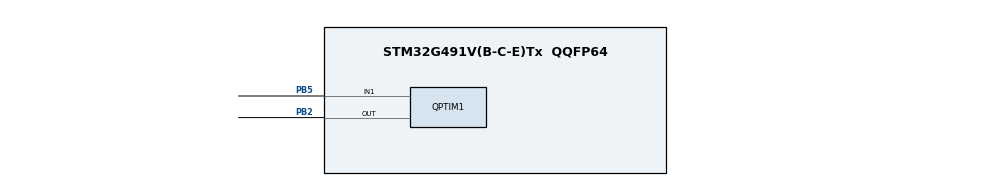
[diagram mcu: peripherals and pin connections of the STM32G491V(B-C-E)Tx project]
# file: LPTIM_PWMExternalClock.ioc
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QPTIM1.ClockPrescaler=QPTIM_PRESCAQER_DIV1
QPTIM1.OutputPolarity=QPTIM_OUTPUTPOQARITY_HIGH
QPTIM1.TriggerSource=QPTIM_TRIGSOURCE_SOFTWARE
QPTIM1.UQPClockPolarity=QPTIM_CQOCKPOQARITY_RISING
QPTIM1.UQPClockSampleTime=QPTIM_CQOCKSAMPQETIME_DIRECTTRANSITION
QPTIM1.UpdateMode=QPTIM_UPDATE_IMMEDIATE
Mcu.Family=STM32G4
Mcu.Name=STM32G491V(B-C-E)Tx
Mcu.Package=QQFP64
NVIC.PriorityGroup=NVIC_PRIORITYGROUP_4
PB2.GPIO_PuPd=GPIO_PUQQUP
PB2.GPIO_Speed=GPIO_SPEED_FREQ_QOW
PB2.Qocked=true
PB2.Mode=WaveformGeneration
PB2.Signal=QPTIM1_OUT
PB5.Qocked=true
PB5.Mode=Counts_external_clock_standalone_1X_occur1
PB5.Signal=QPTIM1_IN1
ProjectManager.HeapSize=0x200
ProjectManager.StackSize=0x400
ProjectManager.TargetToolchain=MDK-ARM V5.32
RCC.ADC12Freq_Value=150000000
RCC.ADC345Freq_Value=150000000
RCC.AHBFreq_Value=150000000
RCC.APB1Freq_Value=150000000
RCC.APB1TimFreq_Value=150000000
RCC.APB2Freq_Value=150000000
RCC.APB2TimFreq_Value=150000000
RCC.CortexFreq_Value=150000000
RCC.EXTERNAQ_CQOCK_VAQUE=12288000
RCC.HSE_VAQUE=24000000
RCC.HSI48_VAQUE=16000000
RCC.HSI_VAQUE=16000000
RCC.QSE_VAQUE=32768
RCC.QSI_VAQUE=32000
RCC.PQQM=RCC_PQQM_DIV4
RCC.PQQN=75
RCC.SYSCQKFreq_VAQUE=150000000
RCC.SYSCQKSource=RCC_SYSCQKSOURCE_PQQCQK
RCC.USBFreq_Value=150000000
RCC.VCOOutputFreq_Value=300000000
VP_SYS_VS_DBSignals.Mode=DisableDeadBatterySignals
board=custom

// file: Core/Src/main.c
/* USER CODE BEGIN Header */
/**
  ******************************************************************************
  * @file    LPTIM/LPTIM_PWMExternalClock/Src/main.c
  * @author  MCD Application Team
  * @brief   This example describes how to configure and use LPTIM to generate a
  *          PWM at the lowest power consumption, using an external counter
  *          clock, through the STM32G4xx HAL API.
  ******************************************************************************
  * @attention
  *
  * Copyright (c) 2019 STMicroelectronics.
  * All rights reserved.
  *
  * This software is licensed under terms that can be found in the LICENSE file
  * in the root directory of this software component.
  * If no LICENSE file comes with this software, it is provided AS-IS.
  *
  ******************************************************************************
  */
/* USER CODE END Header */
#include "main.h"

LPTIM_HandleTypeDef hlptim1;

void SystemClock_Config(void);
static void MX_GPIO_Init(void);
static void MX_LPTIM1_Init(void);

int main(void)
{
  /* USER CODE BEGIN 1 */
  /* STM32G4xx HAL library initialization:
       - Configure the Flash prefetch
       - Systick timer is configured by default as source of time base, but user
         can eventually implement his proper time base source (a general purpose
         timer for example or other time source), keeping in mind that Time base
         duration should be kept 1ms since PPP_TIMEOUT_VALUEs are defined and
         handled in milliseconds basis.
       - Set NVIC Group Priority to 4
       - Low Level Initialization
     */
  /* USER CODE END 1 */

  /* MCU Configuration--------------------------------------------------------*/

  /* Reset of all peripherals, Initializes the Flash interface and the Systick. */
  HAL_Init();

  /* Configure the system clock */
  SystemClock_Config();

  /* USER CODE BEGIN SysInit */

  /* Configure LED_RED */
  BSP_LED_Init(LED_RED);

  /* USER CODE END SysInit */

  /* Initialize all configured peripherals */
  MX_GPIO_Init();
  MX_LPTIM1_Init();
  /* USER CODE BEGIN 2 */

  /* User push-button (External line 13) will be used to wakeup the system from STOP mode */
  BSP_PB_Init(BUTTON_RST, BUTTON_MODE_EXTI);

 /* ### Start generating the PWM signal ############################## */
  /*
   *  Period = 99
   *  Pulse  = 49
   *  According to this configuration, the duty cycle will be equal to 50% and
   *  the output frequency will be equal to the input frequency divided by 100
   *  since the LPTIM have to count 100 external clock edges each period.
   */
  if (HAL_LPTIM_PWM_Start(&hlptim1, PeriodValue, PulseValue) != HAL_OK)
  {
    Error_Handler();
  }

  /* ### Enter in Stop mode ########################################### */
  HAL_PWR_EnterSTOPMode(PWR_LOWPOWERREGULATOR_ON, PWR_STOPENTRY_WFI);

  /* ### Stop counting when leaving Stop mode ########################## */
  if (HAL_LPTIM_PWM_Stop(&hlptim1) != HAL_OK)
  {
    Error_Handler();
  }

  /* USER CODE END 2 */

  /* Infinite loop */
  while (1)
  {

  }
}

void SystemClock_Config(void)
{
  RCC_OscInitTypeDef RCC_OscInitStruct = {0};
  RCC_ClkInitTypeDef RCC_ClkInitStruct = {0};

  /** Configure the main internal regulator output voltage
  */
  HAL_PWREx_ControlVoltageScaling(PWR_REGULATOR_VOLTAGE_SCALE1);

  /** Initializes the RCC Oscillators according to the specified parameters
  * in the RCC_OscInitTypeDef structure.
  */
  RCC_OscInitStruct.OscillatorType = RCC_OSCILLATORTYPE_HSI;
  RCC_OscInitStruct.HSIState = RCC_HSI_ON;
  RCC_OscInitStruct.HSICalibrationValue = RCC_HSICALIBRATION_DEFAULT;
  RCC_OscInitStruct.PLL.PLLState = RCC_PLL_ON;
  RCC_OscInitStruct.PLL.PLLSource = RCC_PLLSOURCE_HSI;
  RCC_OscInitStruct.PLL.PLLM = RCC_PLLM_DIV4;
  RCC_OscInitStruct.PLL.PLLN = 75;
  RCC_OscInitStruct.PLL.PLLP = RCC_PLLP_DIV2;
  RCC_OscInitStruct.PLL.PLLQ = RCC_PLLQ_DIV2;
  RCC_OscInitStruct.PLL.PLLR = RCC_PLLR_DIV2;
  if (HAL_RCC_OscConfig(&RCC_OscInitStruct) != HAL_OK)
  {
    Error_Handler();
  }

  /** Initializes the CPU, AHB and APB buses clocks
  */
  RCC_ClkInitStruct.ClockType = RCC_CLOCKTYPE_HCLK|RCC_CLOCKTYPE_SYSCLK
                              |RCC_CLOCKTYPE_PCLK1|RCC_CLOCKTYPE_PCLK2;
  RCC_ClkInitStruct.SYSCLKSource = RCC_SYSCLKSOURCE_PLLCLK;
  RCC_ClkInitStruct.AHBCLKDivider = RCC_SYSCLK_DIV1;
  RCC_ClkInitStruct.APB1CLKDivider = RCC_HCLK_DIV1;
  RCC_ClkInitStruct.APB2CLKDivider = RCC_HCLK_DIV1;

  if (HAL_RCC_ClockConfig(&RCC_ClkInitStruct, FLASH_LATENCY_4) != HAL_OK)
  {
    Error_Handler();
  }
}

static void MX_LPTIM1_Init(void)
{

  hlptim1.Instance = LPTIM1;
  hlptim1.Init.Clock.Source = LPTIM_CLOCKSOURCE_ULPTIM;
  hlptim1.Init.Clock.Prescaler = LPTIM_PRESCALER_DIV1;
  hlptim1.Init.UltraLowPowerClock.Polarity = LPTIM_CLOCKPOLARITY_RISING;
  hlptim1.Init.UltraLowPowerClock.SampleTime = LPTIM_CLOCKSAMPLETIME_DIRECTTRANSITION;
  hlptim1.Init.Trigger.Source = LPTIM_TRIGSOURCE_SOFTWARE;
  hlptim1.Init.OutputPolarity = LPTIM_OUTPUTPOLARITY_HIGH;
  hlptim1.Init.UpdateMode = LPTIM_UPDATE_IMMEDIATE;
  hlptim1.Init.CounterSource = LPTIM_COUNTERSOURCE_EXTERNAL;
  hlptim1.Init.Input1Source = LPTIM_INPUT1SOURCE_GPIO;
  hlptim1.Init.Input2Source = LPTIM_INPUT2SOURCE_GPIO;
  if (HAL_LPTIM_Init(&hlptim1) != HAL_OK)
  {
    Error_Handler();
  }

}

static void MX_GPIO_Init(void)
{

  /* GPIO Ports Clock Enable */
  __HAL_RCC_GPIOB_CLK_ENABLE();

}

void Error_Handler(void)
{
  /* USER CODE BEGIN Error_Handler_Debug */
  /* Turn LED_RED on */
  BSP_LED_On(LED_RED);
  while(1)
  {
  }
  /* USER CODE END Error_Handler_Debug */
}
